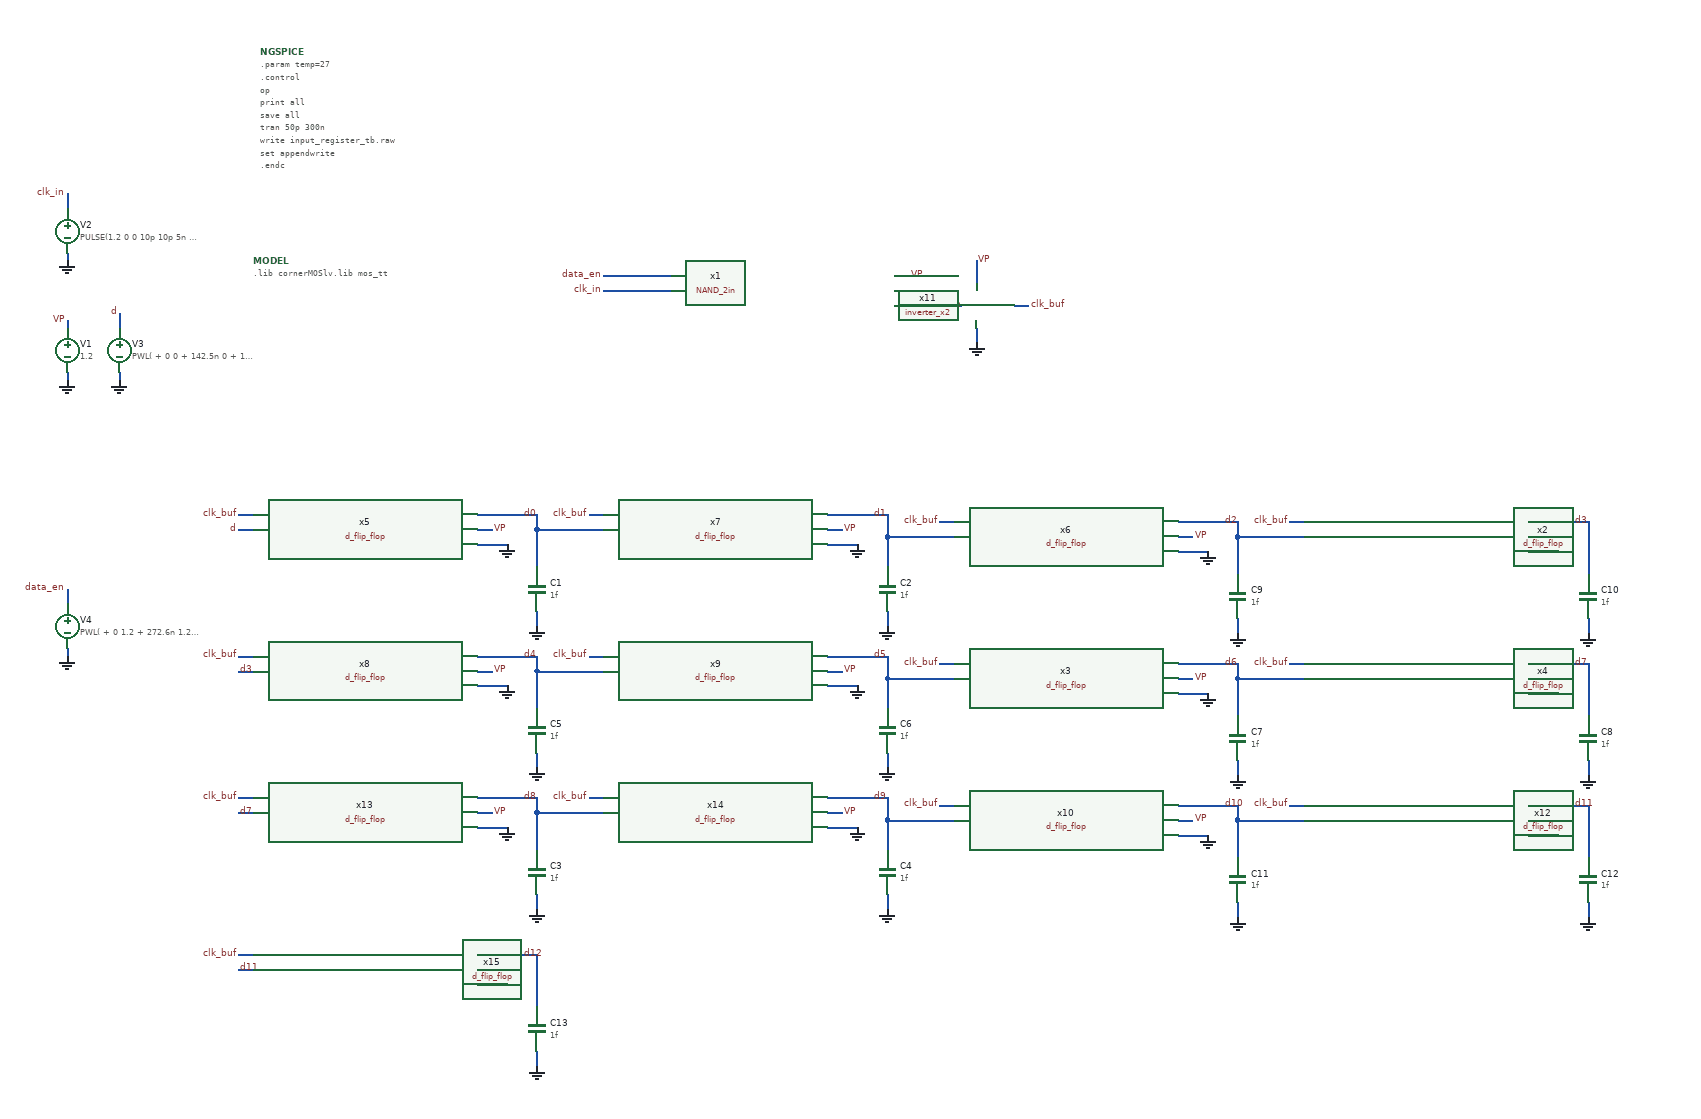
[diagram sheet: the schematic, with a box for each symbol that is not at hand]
v {xschem version=3.4.8RC file_version=1.3}
G {}
K {}
V {}
S {}
F {}
E {}
N -310 70 -310 80 {lab=VP}
N -310 -20 -310 -10 {lab=0}
N 240 370 280 370 {lab=0}
N 240 350 260 350 {lab=VP}
N -80 330 -60 330 {lab=clk_buf}
N -240 60 -240 80 {lab=d}
N -240 140 -240 150 {lab=0}
N -80 350 -60 350 {lab=d}
N 240 330 320 330 {lab=d0}
N 320 350 320 400 {lab=d0}
N 320 350 410 350 {lab=d0}
N 320 330 320 350 {lab=d0}
N 390 330 410 330 {lab=clk_buf}
N 710 330 790 330 {lab=d1}
N 790 360 790 400 {lab=d1}
N 710 370 750 370 {lab=0}
N 710 350 730 350 {lab=VP}
N 790 360 880 360 {lab=d1}
N 860 340 880 340 {lab=clk_buf}
N 1180 340 1260 340 {lab=d2}
N 1260 360 1260 410 {lab=d2}
N 1180 380 1220 380 {lab=0}
N 1180 360 1200 360 {lab=VP}
N 790 330 790 360 {lab=d1}
N 1260 360 1350 360 {lab=d2}
N 1330 340 1350 340 {lab=clk_buf}
N 1650 340 1730 340 {lab=d3}
N 1730 340 1730 410 {lab=d3}
N 1650 380 1690 380 {lab=#net1}
N 1650 360 1670 360 {lab=VP}
N 1260 340 1260 360 {lab=d2}
N 320 650 320 670 {lab=0}
N 240 560 280 560 {lab=0}
N 240 540 260 540 {lab=VP}
N -80 520 -60 520 {lab=clk_buf}
N -80 540 -60 540 {lab=d3}
N 240 520 320 520 {lab=d4}
N 320 540 320 590 {lab=d4}
N 320 540 410 540 {lab=d4}
N 320 520 320 540 {lab=d4}
N 390 520 410 520 {lab=clk_buf}
N 790 650 790 670 {lab=0}
N 710 520 790 520 {lab=d5}
N 790 550 790 590 {lab=d5}
N 710 560 750 560 {lab=0}
N 710 540 730 540 {lab=VP}
N 790 550 880 550 {lab=d5}
N 860 530 880 530 {lab=clk_buf}
N 1260 660 1260 680 {lab=0}
N 1180 530 1260 530 {lab=d6}
N 1260 550 1260 600 {lab=d6}
N 1180 570 1220 570 {lab=0}
N 1180 550 1200 550 {lab=VP}
N 790 520 790 550 {lab=d5}
N 1260 550 1350 550 {lab=d6}
N 1330 530 1350 530 {lab=clk_buf}
N 1730 660 1730 680 {lab=0}
N 1650 530 1730 530 {lab=d7}
N 1730 530 1730 600 {lab=d7}
N 1650 570 1690 570 {lab=#net2}
N 1650 550 1670 550 {lab=VP}
N 1260 530 1260 550 {lab=d6}
N 320 460 320 480 {lab=0}
N 790 460 790 480 {lab=0}
N 1260 470 1260 490 {lab=0}
N 1730 470 1730 490 {lab=0}
N -310 140 -310 150 {lab=0}
N 800 50 890 50 {lab=_clk_un}
N 410 30 500 30 {lab=clk_in}
N 800 30 840 30 {lab=0}
N 800 10 820 10 {lab=VP}
N -310 430 -310 450 {lab=data_en}
N -310 510 -310 520 {lab=0}
N -310 -100 -310 -80 {lab=clk_in}
N 410 10 500 10 {lab=data_en}
N 910 -10 910 20 {lab=VP}
N 910 80 910 100 {lab=0}
N 960 50 980 50 {lab=clk_buf}
N 320 840 320 860 {lab=0}
N 240 750 280 750 {lab=0}
N 240 730 260 730 {lab=VP}
N -80 710 -60 710 {lab=clk_buf}
N -80 730 -60 730 {lab=d7}
N 240 710 320 710 {lab=d8}
N 320 730 320 780 {lab=d8}
N 320 730 410 730 {lab=d8}
N 320 710 320 730 {lab=d8}
N 390 710 410 710 {lab=clk_buf}
N 790 840 790 860 {lab=0}
N 710 710 790 710 {lab=d9}
N 790 740 790 780 {lab=d9}
N 710 750 750 750 {lab=0}
N 710 730 730 730 {lab=VP}
N 790 740 880 740 {lab=d9}
N 860 720 880 720 {lab=clk_buf}
N 1260 850 1260 870 {lab=0}
N 1180 720 1260 720 {lab=d10}
N 1260 740 1260 790 {lab=d10}
N 1180 760 1220 760 {lab=0}
N 1180 740 1200 740 {lab=VP}
N 790 710 790 740 {lab=d9}
N 1260 740 1350 740 {lab=d10}
N 1330 720 1350 720 {lab=clk_buf}
N 1730 850 1730 870 {lab=0}
N 1650 720 1730 720 {lab=d11}
N 1730 720 1730 790 {lab=d11}
N 1650 760 1690 760 {lab=#net3}
N 1650 740 1670 740 {lab=VP}
N 1260 720 1260 740 {lab=d10}
N -80 920 -60 920 {lab=clk_buf}
N 320 1050 320 1070 {lab=0}
N 240 920 320 920 {lab=d12}
N 320 920 320 990 {lab=d12}
N 240 960 280 960 {lab=#net4}
N 240 940 260 940 {lab=VP}
N -80 940 -60 940 {lab=d11}
C {devices/code_shown.sym} -60 -10 0 0 {name=MODEL only_toplevel=true
format="tcleval( @value )"
value=".lib cornerMOSlv.lib mos_tt
"}
C {devices/code_shown.sym} -50 -290 0 0 {name=NGSPICE only_toplevel=false
value="
.param temp=27
.control

op
print all
save all

tran 50p 300n
write input_register_tb.raw
set appendwrite




.endc
"}
C {vsource.sym} -310 110 0 0 {name=V1 value=1.2 savecurrent=false}
C {vsource.sym} -310 -50 0 0 {name=V2 value="PULSE(1.2 0 0 10p 10p 5n 10n)" savecurrent=false}
C {capa.sym} 320 430 0 0 {name=C1
m=1
value=1f
footprint=1206
device="ceramic capacitor"}
C {lab_wire.sym} 980 50 2 0 {name=p2 sig_type=std_logic lab=clk_buf
}
C {lab_wire.sym} -310 70 0 0 {name=p8 sig_type=std_logic lab=VP
}
C {lab_wire.sym} 260 350 2 0 {name=p10 sig_type=std_logic lab=VP
}
C {lab_wire.sym} -80 330 0 0 {name=p7 sig_type=std_logic lab=clk_buf
}
C {lab_wire.sym} 300 330 2 0 {name=p4 sig_type=std_logic lab=d0
}
C {vsource.sym} -240 110 0 0 {name=V3 value="PWL(
+ 0 0 
+ 142.5n 0 
+ 142.51n 1.2
+ 162.5n 1.2 
+ 162.51n 0
+ 172.5n 0
+ 172.51n 1.2
+ 182.5n 1.2
+ 182.51n 0
+ 212.5n 0
+ 212.51n 1.2
+ 222.5n 1.2
+ 222.51n 0
+ 232.5n 0
+ 232.51n 1.2
+ 242.5n 1.2
+ 242.51n 0
+ 262.5n 0
+ 262.51n 1.2
+ 272.5n 1.2
+ 272.51n 0)" savecurrent=false}
C {lab_wire.sym} -240 60 0 0 {name=p6 sig_type=std_logic lab=d
}
C {lab_wire.sym} 390 330 0 0 {name=p1 sig_type=std_logic lab=clk_buf
}
C {capa.sym} 790 430 0 0 {name=C2
m=1
value=1f
footprint=1206
device="ceramic capacitor"}
C {lab_wire.sym} 770 330 2 0 {name=p14 sig_type=std_logic lab=d1
}
C {lab_wire.sym} 730 350 2 0 {name=p17 sig_type=std_logic lab=VP
}
C {lab_wire.sym} 860 340 0 0 {name=p18 sig_type=std_logic lab=clk_buf
}
C {lab_wire.sym} 1240 340 2 0 {name=p20 sig_type=std_logic lab=d2
}
C {lab_wire.sym} 1200 360 2 0 {name=p23 sig_type=std_logic lab=VP
}
C {lab_wire.sym} 1330 340 0 0 {name=p24 sig_type=std_logic lab=clk_buf
}
C {lab_wire.sym} 1710 340 2 0 {name=p26 sig_type=std_logic lab=d3
}
C {lab_wire.sym} 1670 360 2 0 {name=p28 sig_type=std_logic lab=VP
}
C {capa.sym} 320 620 0 0 {name=C5
m=1
value=1f
footprint=1206
device="ceramic capacitor"}
C {lab_wire.sym} 260 540 2 0 {name=p31 sig_type=std_logic lab=VP
}
C {lab_wire.sym} -80 520 0 0 {name=p32 sig_type=std_logic lab=clk_buf
}
C {lab_wire.sym} 300 520 2 0 {name=p33 sig_type=std_logic lab=d4

}
C {lab_wire.sym} 390 520 0 0 {name=p35 sig_type=std_logic lab=clk_buf
}
C {capa.sym} 790 620 0 0 {name=C6
m=1
value=1f
footprint=1206
device="ceramic capacitor"}
C {lab_wire.sym} 770 520 2 0 {name=p37 sig_type=std_logic lab=d5
}
C {lab_wire.sym} 730 540 2 0 {name=p39 sig_type=std_logic lab=VP
}
C {lab_wire.sym} 860 530 0 0 {name=p40 sig_type=std_logic lab=clk_buf
}
C {capa.sym} 1260 630 0 0 {name=C7
m=1
value=1f
footprint=1206
device="ceramic capacitor"}
C {lab_wire.sym} 1240 530 2 0 {name=p42 sig_type=std_logic lab=d6
}
C {lab_wire.sym} 1200 550 2 0 {name=p44 sig_type=std_logic lab=VP
}
C {lab_wire.sym} 1330 530 0 0 {name=p45 sig_type=std_logic lab=clk_buf
}
C {capa.sym} 1730 630 0 0 {name=C8
m=1
value=1f
footprint=1206
device="ceramic capacitor"}
C {lab_wire.sym} 1710 530 2 0 {name=p47 sig_type=std_logic lab=d7
}
C {lab_wire.sym} 1670 550 2 0 {name=p49 sig_type=std_logic lab=VP
}
C {lab_wire.sym} -80 540 2 0 {name=p34 sig_type=std_logic lab=d3
}
C {lab_wire.sym} -80 350 0 0 {name=p12 sig_type=std_logic lab=d
}
C {gnd.sym} 320 670 0 0 {name=l2 lab=0
}
C {gnd.sym} 790 670 0 0 {name=l3 lab=0
}
C {gnd.sym} 1260 680 0 0 {name=l4 lab=0
}
C {gnd.sym} 1730 680 0 0 {name=l5 lab=0
}
C {capa.sym} 1260 440 0 0 {name=C9
m=1
value=1f
footprint=1206
device="ceramic capacitor"}
C {capa.sym} 1730 440 0 0 {name=C10
m=1
value=1f
footprint=1206
device="ceramic capacitor"}
C {gnd.sym} 320 480 0 0 {name=l6 lab=0
}
C {gnd.sym} 790 480 0 0 {name=l7 lab=0
}
C {gnd.sym} 1260 490 0 0 {name=l8 lab=0
}
C {gnd.sym} 1730 490 0 0 {name=l9 lab=0
}
C {gnd.sym} 280 560 0 0 {name=l1 lab=0
}
C {gnd.sym} 280 370 0 0 {name=l10 lab=0
}
C {gnd.sym} 750 560 0 0 {name=l11 lab=0
}
C {gnd.sym} 750 370 0 0 {name=l12 lab=0
}
C {gnd.sym} 1220 570 0 0 {name=l13 lab=0
}
C {gnd.sym} 1220 380 0 0 {name=l14 lab=0
}
C {gnd.sym} 1690 560 0 0 {name=l15 lab=0
}
C {gnd.sym} 1690 370 0 0 {name=l16 lab=0
}
C {gnd.sym} -310 -10 0 0 {name=l17 lab=0
}
C {gnd.sym} -240 150 0 0 {name=l18 lab=0
}
C {gnd.sym} -310 150 0 0 {name=l19 lab=0
}
C {lab_wire.sym} 820 10 2 0 {name=p3 sig_type=std_logic lab=VP
}
C {gnd.sym} 840 30 0 0 {name=l20 lab=0
}
C {vsource.sym} -310 480 0 0 {name=V4 value="PWL(
+ 0 1.2 
+ 272.6n 1.2
+ 272.61n 0)" savecurrent=false}
C {lab_wire.sym} -310 430 0 0 {name=p5 sig_type=std_logic lab=data_en
}
C {gnd.sym} -310 520 0 0 {name=l21 lab=0
}
C {lab_wire.sym} 410 30 0 0 {name=p9 sig_type=std_logic lab=clk_in
}
C {lab_wire.sym} 410 10 0 0 {name=p11 sig_type=std_logic lab=data_en
}
C {lab_wire.sym} -310 -100 0 0 {name=p13 sig_type=std_logic lab=clk_in
}
C {lab_wire.sym} 910 -10 2 0 {name=p15 sig_type=std_logic lab=VP
}
C {gnd.sym} 910 100 0 0 {name=l22 lab=0
}
C {lab_wire.sym} 840 50 2 0 {name=p21 sig_type=std_logic lab=_clk_un
}
C {/foss/designs/CHIP-PLL/divider/schematics/NAND_2in.sym} 650 30 0 0 {name=x1}
C {capa.sym} 320 810 0 0 {name=C3
m=1
value=1f
footprint=1206
device="ceramic capacitor"}
C {lab_wire.sym} 260 730 2 0 {name=p16 sig_type=std_logic lab=VP
}
C {lab_wire.sym} -80 710 0 0 {name=p19 sig_type=std_logic lab=clk_buf
}
C {lab_wire.sym} 300 710 2 0 {name=p22 sig_type=std_logic lab=d8

}
C {lab_wire.sym} 390 710 0 0 {name=p25 sig_type=std_logic lab=clk_buf
}
C {capa.sym} 790 810 0 0 {name=C4
m=1
value=1f
footprint=1206
device="ceramic capacitor"}
C {lab_wire.sym} 770 710 2 0 {name=p27 sig_type=std_logic lab=d9
}
C {lab_wire.sym} 730 730 2 0 {name=p29 sig_type=std_logic lab=VP
}
C {lab_wire.sym} 860 720 0 0 {name=p30 sig_type=std_logic lab=clk_buf
}
C {capa.sym} 1260 820 0 0 {name=C11
m=1
value=1f
footprint=1206
device="ceramic capacitor"}
C {lab_wire.sym} 1240 720 2 0 {name=p36 sig_type=std_logic lab=d10
}
C {lab_wire.sym} 1200 740 2 0 {name=p38 sig_type=std_logic lab=VP
}
C {lab_wire.sym} 1330 720 0 0 {name=p41 sig_type=std_logic lab=clk_buf
}
C {capa.sym} 1730 820 0 0 {name=C12
m=1
value=1f
footprint=1206
device="ceramic capacitor"}
C {lab_wire.sym} 1710 720 2 0 {name=p43 sig_type=std_logic lab=d11
}
C {lab_wire.sym} 1670 740 2 0 {name=p46 sig_type=std_logic lab=VP
}
C {lab_wire.sym} -80 730 2 0 {name=p48 sig_type=std_logic lab=d7
}
C {gnd.sym} 320 860 0 0 {name=l23 lab=0
}
C {gnd.sym} 790 860 0 0 {name=l24 lab=0
}
C {gnd.sym} 1260 870 0 0 {name=l25 lab=0
}
C {gnd.sym} 1730 870 0 0 {name=l26 lab=0
}
C {gnd.sym} 280 750 0 0 {name=l27 lab=0
}
C {gnd.sym} 750 750 0 0 {name=l28 lab=0
}
C {gnd.sym} 1220 760 0 0 {name=l29 lab=0
}
C {gnd.sym} 1690 750 0 0 {name=l30 lab=0
}
C {lab_wire.sym} -80 920 0 0 {name=p50 sig_type=std_logic lab=clk_buf
}
C {capa.sym} 320 1020 0 0 {name=C13
m=1
value=1f
footprint=1206
device="ceramic capacitor"}
C {lab_wire.sym} 300 920 2 0 {name=p51 sig_type=std_logic lab=d12
}
C {lab_wire.sym} 260 940 2 0 {name=p52 sig_type=std_logic lab=VP
}
C {gnd.sym} 320 1070 0 0 {name=l31 lab=0
}
C {gnd.sym} 280 950 0 0 {name=l32 lab=0
}
C {lab_wire.sym} -80 940 2 0 {name=p53 sig_type=std_logic lab=d11
}
C {/foss/designs/CHIP-PLL/divider/schematics/d_flip_flop.sym} 1030 370 0 0 {name=x6}
C {/foss/designs/CHIP-PLL/divider/schematics/d_flip_flop.sym} 1500 370 0 0 {name=x2}
C {/foss/designs/CHIP-PLL/divider/schematics/d_flip_flop.sym} 1030 560 0 0 {name=x3}
C {/foss/designs/CHIP-PLL/divider/schematics/d_flip_flop.sym} 1500 560 0 0 {name=x4}
C {/foss/designs/CHIP-PLL/divider/schematics/d_flip_flop.sym} 90 360 0 0 {name=x5}
C {/foss/designs/CHIP-PLL/divider/schematics/d_flip_flop.sym} 560 360 0 0 {name=x7}
C {/foss/designs/CHIP-PLL/divider/schematics/d_flip_flop.sym} 90 550 0 0 {name=x8}
C {/foss/designs/CHIP-PLL/divider/schematics/d_flip_flop.sym} 560 550 0 0 {name=x9}
C {/foss/designs/CHIP-PLL/divider/schematics/d_flip_flop.sym} 1030 750 0 0 {name=x10}
C {/foss/designs/CHIP-PLL/divider/schematics/d_flip_flop.sym} 1500 750 0 0 {name=x12}
C {/foss/designs/CHIP-PLL/divider/schematics/d_flip_flop.sym} 90 740 0 0 {name=x13}
C {/foss/designs/CHIP-PLL/divider/schematics/d_flip_flop.sym} 560 740 0 0 {name=x14}
C {/foss/designs/CHIP-PLL/divider/schematics/d_flip_flop.sym} 90 950 0 0 {name=x15}
C {/foss/designs/CHIP-PLL/divider/schematics/inverter_x2.sym} 920 50 0 0 {name=x11}
